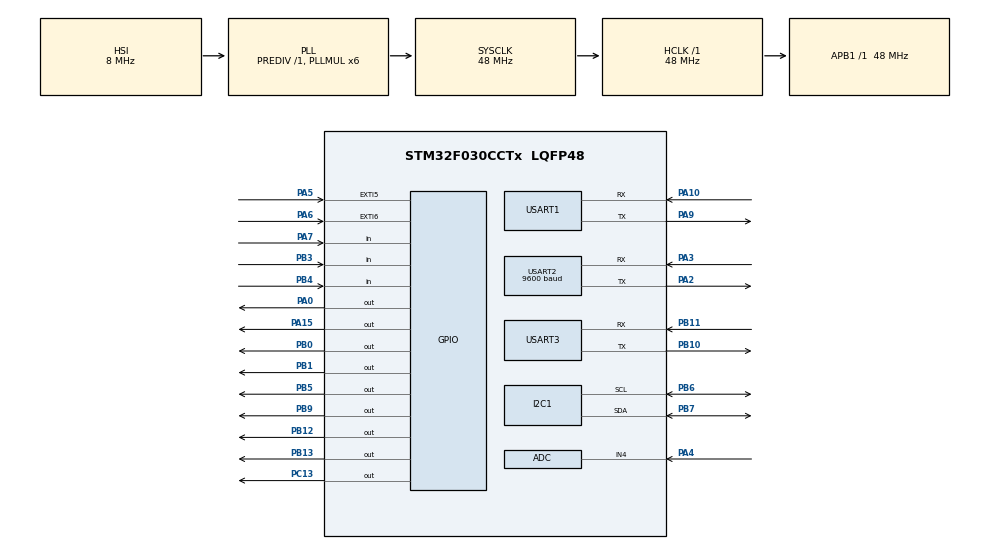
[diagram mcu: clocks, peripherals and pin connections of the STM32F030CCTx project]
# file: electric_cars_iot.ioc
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ADC.ClockPrescaler=ADC_CLOCK_SYNC_PCLK_DIV4
ADC.ContinuousConvMode=ENABLE
ADC.DMAContinuousRequests=ENABLE
ADC.DataAlign=ADC_DATAALIGN_RIGHT
ADC.DiscontinuousConvMode=DISABLE
ADC.EOCSelection=ADC_EOC_SINGLE_CONV
ADC.EnableAnalogWatchDog=false
ADC.ExternalTrigConv=ADC_SOFTWARE_START
ADC.ExternalTrigConvEdge=ADC_EXTERNALTRIGCONVEDGE_NONE
ADC.LowPowerAutoPowerOff=DISABLE
ADC.LowPowerAutoWait=DISABLE
ADC.Overrun=ADC_OVR_DATA_PRESERVED
ADC.Resolution=ADC_RESOLUTION_12B
ADC.SamplingTime=ADC_SAMPLETIME_7CYCLES_5
ADC.ScanConvMode=ADC_SCAN_DIRECTION_FORWARD
Dma.ADC.0.Direction=DMA_PERIPH_TO_MEMORY
Dma.ADC.0.Instance=DMA1_Channel1
Dma.ADC.0.MemDataAlignment=DMA_MDATAALIGN_WORD
Dma.ADC.0.MemInc=DMA_MINC_ENABLE
Dma.ADC.0.Mode=DMA_CIRCULAR
Dma.ADC.0.PeriphDataAlignment=DMA_PDATAALIGN_WORD
Dma.ADC.0.PeriphInc=DMA_PINC_DISABLE
Dma.ADC.0.Priority=DMA_PRIORITY_LOW
Dma.Request0=ADC
FREERTOS.INCLUDE_vTaskDelayUntil=0
FREERTOS.Tasks01=defaultTask,0,512,StartDefaultTask,Default,NULL,Dynamic,NULL,NULL;myTask02,0,256,StartTask02,Default,NULL,Dynamic,NULL,NULL
FREERTOS.configTICK_RATE_HZ=30
FREERTOS.configTOTAL_HEAP_SIZE=15000
FREERTOS.configUSE_IDLE_HOOK=1
FREERTOS.configUSE_TICK_HOOK=0
FREERTOS.configUSE_TIMERS=1
I2C1.Timing=0x20303E5D
IWDG.Prescaler=IWDG_PRESCALER_64
IWDG.Reload=3125
Mcu.Family=STM32F0
Mcu.Name=STM32F030CCTx
Mcu.Package=LQFP48
NVIC.DMA1_Channel1_IRQn=true\:3\:0\:false\:false\:true\:true\:false
NVIC.EXTI4_15_IRQn=true\:3\:0\:false\:false\:true\:true\:true
NVIC.TIM14_IRQn=true\:3\:0\:false\:false\:true\:true\:true
NVIC.TIM3_IRQn=true\:3\:0\:false\:false\:true\:true\:true
NVIC.TIM6_IRQn=true\:0\:0\:false\:false\:true\:false\:false
NVIC.TimeBase=TIM6_IRQn
NVIC.TimeBaseIP=TIM6
NVIC.USART1_IRQn=true\:0\:0\:true\:false\:true\:false\:true
NVIC.USART2_IRQn=true\:3\:0\:false\:false\:true\:true\:true
NVIC.USART3_6_IRQn=true\:3\:0\:false\:false\:true\:true\:true
PA0.Signal=GPIO_Output
PA10.Mode=Asynchronous
PA10.Signal=USART1_RX
PA13.Mode=Serial_Wire
PA13.Signal=SYS_SWDIO
PA14.Mode=Serial_Wire
PA14.Signal=SYS_SWCLK
PA15.Signal=GPIO_Output
PA2.Mode=Asynchronous
PA2.Signal=USART2_TX
PA3.Mode=Asynchronous
PA3.Signal=USART2_RX
PA4.Mode=IN4
PA4.Signal=ADC_IN4
PA5.Signal=GPXTI5
PA6.Signal=GPXTI6
PA7.Signal=GPIO_Input
PA9.Mode=Asynchronous
PA9.Signal=USART1_TX
PB0.Signal=GPIO_Output
PB1.Signal=GPIO_Output
PB10.Mode=Asynchronous
PB10.Signal=USART3_TX
PB11.Mode=Asynchronous
PB11.Signal=USART3_RX
PB12.Signal=GPIO_Output
PB13.Signal=GPIO_Output
PB3.Signal=GPIO_Input
PB4.Signal=GPIO_Input
PB5.Signal=GPIO_Output
PB6.Mode=I2C
PB6.Signal=I2C1_SCL
PB7.Mode=I2C
PB7.Signal=I2C1_SDA
PB9.Signal=GPIO_Output
PC13.Signal=GPIO_Output
PF0-OSC_IN.Mode=HSE-External-Oscillator
PF0-OSC_IN.Signal=RCC_OSC_IN
PF1-OSC_OUT.Mode=HSE-External-Oscillator
PF1-OSC_OUT.Signal=RCC_OSC_OUT
ProjectManager.HeapSize=0x200
ProjectManager.StackSize=0x400
ProjectManager.TargetToolchain=MDK-ARM V5
RCC.AHBFreq_Value=48000000
RCC.APB1Freq_Value=48000000
RCC.APB1TimFreq_Value=48000000
RCC.HCLKFreq_Value=48000000
RCC.I2c1ClockSelection=RCC_I2C1CLKSOURCE_SYSCLK
RCC.PLLMUL=RCC_PLL_MUL6
RCC.RTCClockSelection=RCC_RTCCLKSOURCE_HSE_DIV32
RCC.SYSCLKFreq_VALUE=48000000
RCC.SYSCLKSource=RCC_SYSCLKSOURCE_PLLCLK
RCC.Usart1ClockSelection=RCC_USART1CLKSOURCE_HSI
RTC.AsynchPrediv=99
RTC.SynchPrediv=2499
TIM1.Period=1
TIM1.Prescaler=48-1
TIM14.Period=100-1
TIM14.Prescaler=4800-1
TIM3.Period=10000-1
TIM3.Prescaler=4800-1
USART1.VirtualMode-Asynchronous=VM_ASYNC
USART1.WordLength=WORDLENGTH_8B
USART2.BaudRate=9600
USART2.VirtualMode-Asynchronous=VM_ASYNC
USART2.WordLength=WORDLENGTH_8B
USART3.VirtualMode-Asynchronous=VM_ASYNC
USART3.WordLength=WORDLENGTH_8B
VP_FREERTOS_VS_ENABLE.Mode=Enabled
VP_IWDG_VS_IWDG.Mode=IWDG_Activate
VP_RTC_VS_RTC_Activate.Mode=RTC_Enabled
VP_RTC_VS_RTC_Calendar.Mode=RTC_Calendar
VP_SYS_VS_tim6.Mode=TIM6
VP_TIM14_VS_ClockSourceINT.Mode=Enable_Timer
VP_TIM1_VS_ClockSourceINT.Mode=Internal
VP_TIM3_VS_ClockSourceINT.Mode=Internal
board=electric_cars_iot

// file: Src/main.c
/**
  ******************************************************************************
  * @file           : main.c
  * @brief          : Main program body
  ******************************************************************************
  * This notice applies to any and all portions of this file
  * that are not between comment pairs USER CODE BEGIN and
  * USER CODE END. Other portions of this file, whether
  * inserted by the user or by software development tools
  * are owned by their respective copyright owners.
  *
  * Copyright (c) 2018 STMicroelectronics International N.V.
  * All rights reserved.
  *
  * Redistribution and use in source and binary forms, with or without
  * modification, are permitted, provided that the following conditions are met:
  *
  * 1. Redistribution of source code must retain the above copyright notice,
  *    this list of conditions and the following disclaimer.
  * 2. Redistributions in binary form must reproduce the above copyright notice,
  *    this list of conditions and the following disclaimer in the documentation
  *    and/or other materials provided with the distribution.
  * 3. Neither the name of STMicroelectronics nor the names of other
  *    contributors to this software may be used to endorse or promote products
  *    derived from this software without specific written permission.
  * 4. This software, including modifications and/or derivative works of this
  *    software, must execute solely and exclusively on microcontroller or
  *    microprocessor devices manufactured by or for STMicroelectronics.
  * 5. Redistribution and use of this software other than as permitted under
  *    this license is void and will automatically terminate your rights under
  *    this license.
  *
  * THIS SOFTWARE IS PROVIDED BY STMICROELECTRONICS AND CONTRIBUTORS "AS IS"
  * AND ANY EXPRESS, IMPLIED OR STATUTORY WARRANTIES, INCLUDING, BUT NOT
  * LIMITED TO, THE IMPLIED WARRANTIES OF MERCHANTABILITY, FITNESS FOR A
  * PARTICULAR PURPOSE AND NON-INFRINGEMENT OF THIRD PARTY INTELLECTUAL PROPERTY
  * RIGHTS ARE DISCLAIMED TO THE FULLEST EXTENT PERMITTED BY LAW. IN NO EVENT
  * SHALL STMICROELECTRONICS OR CONTRIBUTORS BE LIABLE FOR ANY DIRECT, INDIRECT,
  * INCIDENTAL, SPECIAL, EXEMPLARY, OR CONSEQUENTIAL DAMAGES (INCLUDING, BUT NOT
  * LIMITED TO, PROCUREMENT OF SUBSTITUTE GOODS OR SERVICES; LOSS OF USE, DATA,
  * OR PROFITS; OR BUSINESS INTERRUPTION) HOWEVER CAUSED AND ON ANY THEORY OF
  * LIABILITY, WHETHER IN CONTRACT, STRICT LIABILITY, OR TORT (INCLUDING
  * NEGLIGENCE OR OTHERWISE) ARISING IN ANY WAY OUT OF THE USE OF THIS SOFTWARE,
  * EVEN IF ADVISED OF THE POSSIBILITY OF SUCH DAMAGE.
  *
  ******************************************************************************
  */
#include "main.h"
#include "stm32f0xx_hal.h"
#include "cmsis_os.h"

/* USER CODE BEGIN Includes */
#include "usart.h"
#include "Iot_Hub.h"
#include "protocol.h"
#include "adc.h"
#include "exti.h"
#include "voice.h"
#include "gpio.h"
#include "flash.h"
#include "bt_app.h"
#include "queen.h"
#include "control_app.h"

/* USER CODE END Includes */

ADC_HandleTypeDef hadc;
DMA_HandleTypeDef hdma_adc;

I2C_HandleTypeDef hi2c1;

IWDG_HandleTypeDef hiwdg;

RTC_HandleTypeDef hrtc;

TIM_HandleTypeDef htim1;
TIM_HandleTypeDef htim3;
TIM_HandleTypeDef htim14;

UART_HandleTypeDef huart1;
UART_HandleTypeDef huart2;
UART_HandleTypeDef huart3;

osThreadId defaultTaskHandle;
osThreadId myTask02Handle;

/* USER CODE BEGIN PV */
/* Private variables ---------------------------------------------------------*/
uint8_t usart1_recbuf, usart2_recbuf,usart3_recbuf;
uint8_t tim3_delay3s;
uint16_t tim14_delay900ms,tim14_delay500ms,tim14_delay10ms, tim14_delay4s,tim14_delay8s;
uint8_t flag_delay3s, flag_delay1s, flag_sendlock;
uint32_t adc_val[64];
uint16_t batvol;
uint64_t rotate_bak, mileage_bak, shake_bak;
uint8_t first_pwr;

extern uint8_t login_protect_timeout;
extern uint8_t flag_alarm;
extern uint8_t flag_delay8s;

/* USER CODE END PV */

void SystemClock_Config(void);
static void MX_GPIO_Init(void);
static void MX_DMA_Init(void);
static void MX_USART1_UART_Init(void);
static void MX_USART2_UART_Init(void);
static void MX_USART3_UART_Init(void);
static void MX_ADC_Init(void);
static void MX_TIM3_Init(void);
static void MX_TIM1_Init(void);
static void MX_TIM14_Init(void);
static void MX_I2C1_Init(void);
static void MX_IWDG_Init(void);
static void MX_RTC_Init(void);
void StartDefaultTask(void const * argument);
void StartTask02(void const * argument);

/* USER CODE BEGIN 0 */
void delay_us(uint32_t n_10us);
void init_all(void)
{
	init_flash();
 	bt_init();
}
/* USER CODE END 0 */

int main(void)
{
  HAL_Init();
  SystemClock_Config();

  MX_GPIO_Init();
  MX_DMA_Init();
  MX_USART1_UART_Init();
  MX_USART2_UART_Init();
  MX_USART3_UART_Init();
  MX_I2C1_Init();
  MX_ADC_Init();
  MX_TIM3_Init();
  MX_TIM1_Init();
  MX_TIM14_Init();
  MX_IWDG_Init();
  MX_RTC_Init();

  init_all();

  osThreadDef(defaultTask, StartDefaultTask, osPriorityNormal, 0, 2048);
  defaultTaskHandle = osThreadCreate(osThread(defaultTask), NULL);

  osThreadDef(myTask02, StartTask02, osPriorityNormal, 0, 1024);
  myTask02Handle = osThreadCreate(osThread(myTask02), NULL);

  osKernelStart();

  while (1)
  {
  }

}

void SystemClock_Config(void)
{

  RCC_OscInitTypeDef RCC_OscInitStruct;
  RCC_ClkInitTypeDef RCC_ClkInitStruct;
  RCC_PeriphCLKInitTypeDef PeriphClkInit;

    /**Initializes the CPU, AHB and APB busses clocks
    */
  RCC_OscInitStruct.OscillatorType = RCC_OSCILLATORTYPE_HSI|RCC_OSCILLATORTYPE_LSI
                              |RCC_OSCILLATORTYPE_HSE;
  RCC_OscInitStruct.HSEState = RCC_HSE_ON;
  RCC_OscInitStruct.HSIState = RCC_HSI_ON;
  RCC_OscInitStruct.HSICalibrationValue = 16;
  RCC_OscInitStruct.LSIState = RCC_LSI_ON;
  RCC_OscInitStruct.PLL.PLLState = RCC_PLL_ON;
  RCC_OscInitStruct.PLL.PLLSource = RCC_PLLSOURCE_HSI;
  RCC_OscInitStruct.PLL.PLLMUL = RCC_PLL_MUL6;
  RCC_OscInitStruct.PLL.PREDIV = RCC_PREDIV_DIV1;
  if (HAL_RCC_OscConfig(&RCC_OscInitStruct) != HAL_OK)
  {
    _Error_Handler(__FILE__, __LINE__);
  }

    /**Initializes the CPU, AHB and APB busses clocks
    */
  RCC_ClkInitStruct.ClockType = RCC_CLOCKTYPE_HCLK|RCC_CLOCKTYPE_SYSCLK
                              |RCC_CLOCKTYPE_PCLK1;
  RCC_ClkInitStruct.SYSCLKSource = RCC_SYSCLKSOURCE_PLLCLK;
  RCC_ClkInitStruct.AHBCLKDivider = RCC_SYSCLK_DIV1;
  RCC_ClkInitStruct.APB1CLKDivider = RCC_HCLK_DIV1;

  if (HAL_RCC_ClockConfig(&RCC_ClkInitStruct, FLASH_LATENCY_1) != HAL_OK)
  {
    _Error_Handler(__FILE__, __LINE__);
  }

  PeriphClkInit.PeriphClockSelection = RCC_PERIPHCLK_USART1|RCC_PERIPHCLK_I2C1
                              |RCC_PERIPHCLK_RTC;
  PeriphClkInit.Usart1ClockSelection = RCC_USART1CLKSOURCE_HSI;
  PeriphClkInit.I2c1ClockSelection = RCC_I2C1CLKSOURCE_SYSCLK;
  PeriphClkInit.RTCClockSelection = RCC_RTCCLKSOURCE_HSE_DIV32;
  if (HAL_RCCEx_PeriphCLKConfig(&PeriphClkInit) != HAL_OK)
  {
    _Error_Handler(__FILE__, __LINE__);
  }

    /**Configure the Systick interrupt time
    */
  HAL_SYSTICK_Config(HAL_RCC_GetHCLKFreq()/1000);

    /**Configure the Systick
    */
  HAL_SYSTICK_CLKSourceConfig(SYSTICK_CLKSOURCE_HCLK);

  /* SysTick_IRQn interrupt configuration */
  HAL_NVIC_SetPriority(SysTick_IRQn, 3, 0);
}

/* ADC init function */
static void MX_ADC_Init(void)
{

  ADC_ChannelConfTypeDef sConfig;

    /**Configure the global features of the ADC (Clock, Resolution, Data Alignment and number of conversion)
    */
  hadc.Instance = ADC1;
  hadc.Init.ClockPrescaler = ADC_CLOCK_SYNC_PCLK_DIV4;
  hadc.Init.Resolution = ADC_RESOLUTION_12B;
  hadc.Init.DataAlign = ADC_DATAALIGN_RIGHT;
  hadc.Init.ScanConvMode = ADC_SCAN_DIRECTION_FORWARD;
  hadc.Init.EOCSelection = ADC_EOC_SINGLE_CONV;
  hadc.Init.LowPowerAutoWait = DISABLE;
  hadc.Init.LowPowerAutoPowerOff = DISABLE;
  hadc.Init.ContinuousConvMode = ENABLE;
  hadc.Init.DiscontinuousConvMode = DISABLE;
  hadc.Init.ExternalTrigConv = ADC_SOFTWARE_START;
  hadc.Init.ExternalTrigConvEdge = ADC_EXTERNALTRIGCONVEDGE_NONE;
  hadc.Init.DMAContinuousRequests = ENABLE;
  hadc.Init.Overrun = ADC_OVR_DATA_PRESERVED;
  if (HAL_ADC_Init(&hadc) != HAL_OK)
  {
    _Error_Handler(__FILE__, __LINE__);
  }

    /**Configure for the selected ADC regular channel to be converted.
    */
  sConfig.Channel = ADC_CHANNEL_4;
  sConfig.Rank = ADC_RANK_CHANNEL_NUMBER;
  sConfig.SamplingTime = ADC_SAMPLETIME_7CYCLES_5;
  if (HAL_ADC_ConfigChannel(&hadc, &sConfig) != HAL_OK)
  {
    _Error_Handler(__FILE__, __LINE__);
  }

}

/* IWDG init function */
static void MX_IWDG_Init(void)
{

  hiwdg.Instance = IWDG;
  hiwdg.Init.Prescaler = IWDG_PRESCALER_64;
  hiwdg.Init.Window = 4095;
  hiwdg.Init.Reload = 3125;
  if (HAL_IWDG_Init(&hiwdg) != HAL_OK)
  {
    _Error_Handler(__FILE__, __LINE__);
  }

}

/* RTC init function */
static void MX_RTC_Init(void)
{

  RTC_TimeTypeDef sTime;
  RTC_DateTypeDef sDate;

    /**Initialize RTC Only
    */
  hrtc.Instance = RTC;
  hrtc.Init.HourFormat = RTC_HOURFORMAT_24;
  hrtc.Init.AsynchPrediv = 99;
  hrtc.Init.SynchPrediv = 2499;
  hrtc.Init.OutPut = RTC_OUTPUT_DISABLE;
  hrtc.Init.OutPutPolarity = RTC_OUTPUT_POLARITY_HIGH;
  hrtc.Init.OutPutType = RTC_OUTPUT_TYPE_OPENDRAIN;
  if (HAL_RTC_Init(&hrtc) != HAL_OK)
  {
    _Error_Handler(__FILE__, __LINE__);
  }

    /**Initialize RTC and set the Time and Date
    */
  sTime.Hours = 0x0;
  sTime.Minutes = 0x0;
  sTime.Seconds = 0x0;
  sTime.DayLightSaving = RTC_DAYLIGHTSAVING_NONE;
  sTime.StoreOperation = RTC_STOREOPERATION_RESET;
  if (HAL_RTC_SetTime(&hrtc, &sTime, RTC_FORMAT_BCD) != HAL_OK)
  {
    _Error_Handler(__FILE__, __LINE__);
  }

  sDate.WeekDay = RTC_WEEKDAY_MONDAY;
  sDate.Month = RTC_MONTH_JANUARY;
  sDate.Date = 0x1;
  sDate.Year = 0x0;

  if (HAL_RTC_SetDate(&hrtc, &sDate, RTC_FORMAT_BCD) != HAL_OK)
  {
    _Error_Handler(__FILE__, __LINE__);
  }

}

/* TIM1 init function */
static void MX_TIM1_Init(void)
{

  TIM_ClockConfigTypeDef sClockSourceConfig;
  TIM_MasterConfigTypeDef sMasterConfig;

  htim1.Instance = TIM1;
  htim1.Init.Prescaler = 48-1;
  htim1.Init.CounterMode = TIM_COUNTERMODE_UP;
  htim1.Init.Period = 1;
  htim1.Init.ClockDivision = TIM_CLOCKDIVISION_DIV1;
  htim1.Init.RepetitionCounter = 0;
  htim1.Init.AutoReloadPreload = TIM_AUTORELOAD_PRELOAD_DISABLE;
  if (HAL_TIM_Base_Init(&htim1) != HAL_OK)
  {
    _Error_Handler(__FILE__, __LINE__);
  }

  sClockSourceConfig.ClockSource = TIM_CLOCKSOURCE_INTERNAL;
  if (HAL_TIM_ConfigClockSource(&htim1, &sClockSourceConfig) != HAL_OK)
  {
    _Error_Handler(__FILE__, __LINE__);
  }

  sMasterConfig.MasterOutputTrigger = TIM_TRGO_RESET;
  sMasterConfig.MasterSlaveMode = TIM_MASTERSLAVEMODE_DISABLE;
  if (HAL_TIMEx_MasterConfigSynchronization(&htim1, &sMasterConfig) != HAL_OK)
  {
    _Error_Handler(__FILE__, __LINE__);
  }

}

/* TIM3 init function */
static void MX_TIM3_Init(void)
{

  TIM_ClockConfigTypeDef sClockSourceConfig;
  TIM_MasterConfigTypeDef sMasterConfig;

  htim3.Instance = TIM3;
  htim3.Init.Prescaler = 4800-1;
  htim3.Init.CounterMode = TIM_COUNTERMODE_UP;
  htim3.Init.Period = 10000-1;
  htim3.Init.ClockDivision = TIM_CLOCKDIVISION_DIV1;
  htim3.Init.AutoReloadPreload = TIM_AUTORELOAD_PRELOAD_DISABLE;
  if (HAL_TIM_Base_Init(&htim3) != HAL_OK)
  {
    _Error_Handler(__FILE__, __LINE__);
  }

  sClockSourceConfig.ClockSource = TIM_CLOCKSOURCE_INTERNAL;
  if (HAL_TIM_ConfigClockSource(&htim3, &sClockSourceConfig) != HAL_OK)
  {
    _Error_Handler(__FILE__, __LINE__);
  }

  sMasterConfig.MasterOutputTrigger = TIM_TRGO_RESET;
  sMasterConfig.MasterSlaveMode = TIM_MASTERSLAVEMODE_DISABLE;
  if (HAL_TIMEx_MasterConfigSynchronization(&htim3, &sMasterConfig) != HAL_OK)
  {
    _Error_Handler(__FILE__, __LINE__);
  }

}

/* TIM14 init function */
static void MX_TIM14_Init(void)
{

  htim14.Instance = TIM14;
  htim14.Init.Prescaler = 4800-1;
  htim14.Init.CounterMode = TIM_COUNTERMODE_UP;
  htim14.Init.Period = 10-1;
  htim14.Init.ClockDivision = TIM_CLOCKDIVISION_DIV1;
  htim14.Init.AutoReloadPreload = TIM_AUTORELOAD_PRELOAD_DISABLE;
  if (HAL_TIM_Base_Init(&htim14) != HAL_OK)
  {
    _Error_Handler(__FILE__, __LINE__);
  }

}
static void MX_I2C1_Init(void)
{

  hi2c1.Instance = I2C1;
  hi2c1.Init.Timing = 0x20303E5D;
  hi2c1.Init.OwnAddress1 = 0;
  hi2c1.Init.AddressingMode = I2C_ADDRESSINGMODE_7BIT;
  hi2c1.Init.DualAddressMode = I2C_DUALADDRESS_DISABLE;
  hi2c1.Init.OwnAddress2 = 0;
  hi2c1.Init.OwnAddress2Masks = I2C_OA2_NOMASK;
  hi2c1.Init.GeneralCallMode = I2C_GENERALCALL_DISABLE;
  hi2c1.Init.NoStretchMode = I2C_NOSTRETCH_DISABLE;
  if (HAL_I2C_Init(&hi2c1) != HAL_OK)
  {
    _Error_Handler(__FILE__, __LINE__);
  }

    /**Configure Analogue filter
    */
  if (HAL_I2CEx_ConfigAnalogFilter(&hi2c1, I2C_ANALOGFILTER_ENABLE) != HAL_OK)
  {
    _Error_Handler(__FILE__, __LINE__);
  }

    /**Configure Digital filter
    */
  if (HAL_I2CEx_ConfigDigitalFilter(&hi2c1, 0) != HAL_OK)
  {
    _Error_Handler(__FILE__, __LINE__);
  }

}

/* USART1 init function */
static void MX_USART1_UART_Init(void)
{

  huart1.Instance = USART1;
  huart1.Init.BaudRate = 115200;
  huart1.Init.WordLength = UART_WORDLENGTH_8B;
  huart1.Init.StopBits = UART_STOPBITS_1;
  huart1.Init.Parity = UART_PARITY_NONE;
  huart1.Init.Mode = UART_MODE_TX_RX;
  huart1.Init.HwFlowCtl = UART_HWCONTROL_NONE;
  huart1.Init.OverSampling = UART_OVERSAMPLING_16;
  huart1.Init.OneBitSampling = UART_ONE_BIT_SAMPLE_DISABLE;
  huart1.AdvancedInit.AdvFeatureInit = UART_ADVFEATURE_NO_INIT;
  if (HAL_UART_Init(&huart1) != HAL_OK)
  {
    _Error_Handler(__FILE__, __LINE__);
  }
  HAL_UART_Receive_IT(&huart1, (uint8_t *)&usart1_recbuf, 1);

}

/* USART2 init function */
static void MX_USART2_UART_Init(void)
{

  huart2.Instance = USART2;
  huart2.Init.BaudRate = 9600;
  huart2.Init.WordLength = UART_WORDLENGTH_8B;
  huart2.Init.StopBits = UART_STOPBITS_1;
  huart2.Init.Parity = UART_PARITY_NONE;
  huart2.Init.Mode = UART_MODE_TX_RX;
  huart2.Init.HwFlowCtl = UART_HWCONTROL_NONE;
  huart2.Init.OverSampling = UART_OVERSAMPLING_16;
  huart2.Init.OneBitSampling = UART_ONE_BIT_SAMPLE_DISABLE;
  huart2.AdvancedInit.AdvFeatureInit = UART_ADVFEATURE_NO_INIT;
  if (HAL_UART_Init(&huart2) != HAL_OK)
  {
    _Error_Handler(__FILE__, __LINE__);
  }

}

/* USART3 init function */
static void MX_USART3_UART_Init(void)
{
  huart3.Instance = USART3;
  huart3.Init.BaudRate = 115200;
  huart3.Init.WordLength = UART_WORDLENGTH_8B;
  huart3.Init.StopBits = UART_STOPBITS_1;
  huart3.Init.Parity = UART_PARITY_NONE;
  huart3.Init.Mode = UART_MODE_TX_RX;
  huart3.Init.HwFlowCtl = UART_HWCONTROL_NONE;
  huart3.Init.OverSampling = UART_OVERSAMPLING_16;
  huart3.Init.OneBitSampling = UART_ONE_BIT_SAMPLE_DISABLE;
  huart3.AdvancedInit.AdvFeatureInit = UART_ADVFEATURE_NO_INIT;
  if (HAL_UART_Init(&huart3) != HAL_OK)
  {
    _Error_Handler(__FILE__, __LINE__);
  }

}

static void MX_DMA_Init(void)
{
  /* DMA controller clock enable */
  __HAL_RCC_DMA1_CLK_ENABLE();

  /* DMA interrupt init */
  /* DMA1_Channel1_IRQn interrupt configuration */
  HAL_NVIC_SetPriority(DMA1_Channel1_IRQn, 3, 0);
  HAL_NVIC_EnableIRQ(DMA1_Channel1_IRQn);

}

/** Configure pins as
        * Analog
        * Input
        * Output
        * EVENT_OUT
        * EXTI
*/
static void MX_GPIO_Init(void)
{

  GPIO_InitTypeDef GPIO_InitStruct;

  /* GPIO Ports Clock Enable */
  __HAL_RCC_GPIOC_CLK_ENABLE();
  __HAL_RCC_GPIOF_CLK_ENABLE();
  __HAL_RCC_GPIOA_CLK_ENABLE();
  __HAL_RCC_GPIOB_CLK_ENABLE();

  /*Configure GPIO pin Output Level */
  HAL_GPIO_WritePin(GPIOC, GPIO_PIN_13, GPIO_PIN_RESET);

  /*Configure GPIO pin Output Level */
  HAL_GPIO_WritePin(GPIOA, GPIO_PIN_0|GPIO_PIN_1|GPIO_PIN_11|GPIO_PIN_15|GPIO_PIN_12, GPIO_PIN_RESET);

  /*Configure GPIO pin Output Level */
  HAL_GPIO_WritePin(GPIOB, GPIO_PIN_0|GPIO_PIN_1|GPIO_PIN_12|GPIO_PIN_13
                          |GPIO_PIN_5|GPIO_PIN_9, GPIO_PIN_RESET);

  /*Configure GPIO pin : PC13 */
  GPIO_InitStruct.Pin = GPIO_PIN_13;
  GPIO_InitStruct.Mode = GPIO_MODE_OUTPUT_PP;
  GPIO_InitStruct.Pull = GPIO_NOPULL;
  GPIO_InitStruct.Speed = GPIO_SPEED_FREQ_LOW;
  HAL_GPIO_Init(GPIOC, &GPIO_InitStruct);

  /*Configure GPIO pins : PA0 PA15 */
  GPIO_InitStruct.Pin = GPIO_PIN_0|GPIO_PIN_1|GPIO_PIN_11|GPIO_PIN_15|GPIO_PIN_12;
  GPIO_InitStruct.Mode = GPIO_MODE_OUTPUT_PP;
  GPIO_InitStruct.Pull = GPIO_NOPULL;
  GPIO_InitStruct.Speed = GPIO_SPEED_FREQ_LOW;
  HAL_GPIO_Init(GPIOA, &GPIO_InitStruct);

  /*Configure GPIO pins : PA5 PA6 */
  GPIO_InitStruct.Pin = GPIO_PIN_5|GPIO_PIN_6|GPIO_PIN_8;
  GPIO_InitStruct.Mode = GPIO_MODE_IT_RISING;
  GPIO_InitStruct.Pull = GPIO_NOPULL;
  HAL_GPIO_Init(GPIOA, &GPIO_InitStruct);

  /*Configure GPIO pin : PA7 */
  GPIO_InitStruct.Pin = GPIO_PIN_7;
  GPIO_InitStruct.Mode = GPIO_MODE_INPUT;
  GPIO_InitStruct.Pull = GPIO_NOPULL;
  HAL_GPIO_Init(GPIOA, &GPIO_InitStruct);

  /*Configure GPIO pins : PB0 PB1 PB12 PB13
                           PB5 PB9 */
  GPIO_InitStruct.Pin = GPIO_PIN_0|GPIO_PIN_1|GPIO_PIN_12|GPIO_PIN_13
                          |GPIO_PIN_5|GPIO_PIN_9;
  GPIO_InitStruct.Mode = GPIO_MODE_OUTPUT_PP;
  GPIO_InitStruct.Pull = GPIO_NOPULL;
  GPIO_InitStruct.Speed = GPIO_SPEED_FREQ_LOW;
  HAL_GPIO_Init(GPIOB, &GPIO_InitStruct);

  /*Configure GPIO pins : PB3 PB4 */
  GPIO_InitStruct.Pin = GPIO_PIN_3|GPIO_PIN_4;
  GPIO_InitStruct.Mode = GPIO_MODE_INPUT;
  GPIO_InitStruct.Pull = GPIO_NOPULL;
  HAL_GPIO_Init(GPIOB, &GPIO_InitStruct);

  /* EXTI interrupt init*/
  HAL_NVIC_SetPriority(EXTI4_15_IRQn, 3, 0);
  HAL_NVIC_EnableIRQ(EXTI4_15_IRQn);

}

/* USER CODE BEGIN 4 */
/**
  * @brief  Rx Transfer completed callback
  * @param  UartHandle: UART handle
  * @note   This example shows a simple way to report end of DMA Rx transfer, and
  *         you can add your own implementation.
  * @retval None
  */
void HAL_UART_RxCpltCallback(UART_HandleTypeDef *UartHandle)
{
  /* Set transmission flag: transfer complete */
	if (UartHandle->Instance == USART1)
	{
		module_recv_buffer[module_recv_write_index] = usart1_recbuf; //将接收到的字符串存到缓存中
		module_recv_write_index++;
		if(module_recv_write_index >= MODULE_BUFFER_SIZE)       			//如果缓存满,将缓存指针指向缓存的首地址
		{
			module_recv_write_index = 0;
		}
		 HAL_UART_Receive_IT(&huart1, (uint8_t *)&usart1_recbuf, 1);
       	}
	if (UartHandle->Instance == USART2)
	{
		Uart2_buf.Data[0]= usart2_recbuf;
		PushElement(&RxUart2_Queue,Uart2_buf,1);//将接收到的数据压入队列中
		HAL_UART_Receive_IT(&huart2, &usart2_recbuf, 1);
	}
	if (UartHandle->Instance == USART3)
	{
		Uart3_buf.Data[0]= usart3_recbuf;
		PushElement(&RxUart3_Queue,Uart3_buf,1);//将接收到的数据压入队列中
		HAL_UART_Receive_IT(&huart3, &usart3_recbuf, 1);
	}
}
/* USER CODE END 4 */

/* StartDefaultTask function */
void StartDefaultTask(void const * argument)
{
  /* USER CODE BEGIN 5 */
  	first_pwr = 1;
  	InitCircleQueue(&at_send_Queue);	                           //初始化队列

	/* Infinite loop */
	for(;;)
	{
		voice_process();
		if(g_flash.mode==0)	//正常模式
		{
			at_process();
		}
		else if(g_flash.mode==1)	//测试模式
		{
			test_process();
	    	}
		osDelay(1);
	}
  /* USER CODE END 5 */
}

/* StartTask02 function */
void StartTask02(void const * argument)
{
  /* USER CODE BEGIN StartTask02 */
	HAL_TIM_Base_Start_IT(&htim14);
  	HAL_TIM_Base_Start_IT(&htim3);
	HAL_ADCEx_Calibration_Start(&hadc);
	HAL_ADC_Start_DMA(&hadc, (uint32_t*)&adc_val, 64);
	InitCircleQueue(&RxUart2_Queue);	                           //初始化队列
	HAL_UART_Receive_IT(&huart2, (uint8_t *)&usart2_recbuf, 1);
	InitCircleQueue(&RxUart3_Queue);	                           //初始化队列
	HAL_UART_Receive_IT(&huart3, (uint8_t *)&usart3_recbuf, 1);
	HAL_Delay(2000);
	flag_alarm = 0;	//延时一会再启动震动告警

  for(;;)
  {
  	if(g_flash.mode==0)	//正常模式
	{
	        tangze_lock_bike();
	        tangze_unlock_bike();
	        battery_lock();
	        motorlock_process();
	        shake_process();
	//	key_check_process();
		gsm_led_process();
	        gps_led_process();
		gb_speed_process();
  	}
	uart2_process();
	uart3_process();

        osDelay(1);
  }

}

void HAL_TIM_PeriodElapsedCallback(TIM_HandleTypeDef *htim)
{
  /* USER CODE BEGIN Callback 0 */
	if (htim->Instance == TIM14)
	{
		if (flag_delay900ms)
			tim14_delay900ms ++;
		if (tim14_delay900ms >= 800)
		{
			tim14_delay900ms = 0;
			if (flag_lock == 1)
			{
				flag_delay_lock = 1;
			}
			else if (flag_lock == 2)
			{
				flag_delay_unlock = 1;
			}
		}

		if (flag_delay500ms)
			tim14_delay500ms ++;
		if (tim14_delay500ms >= 500)
		{
			tim14_delay500ms = 0;
			flag_batlock = 1;
		}
		if (flag_delay10ms)
			tim14_delay10ms ++;
		if (tim14_delay10ms >= 1)
		{
			tim14_delay10ms = 0;
			flag_motorlock = 1;
		}
		if (flag_delay4s)
			tim14_delay4s++;
		if (tim14_delay4s >= 4000)
		{
			tim14_delay4s = 0;
			flag_motorlock2 = 1;
		}

		if (flag_delay8s)
			tim14_delay8s++;
		if (tim14_delay8s >= 8000)
		{
			tim14_delay8s = 0;
			flag_alarm = 0;
			flag_delay8s = 0;
		}

	}

	/* USER CODE END Callback 0 */
	if (htim->Instance == TIM6)
	{
	HAL_IncTick();
	}
  	/* USER CODE BEGIN Callback 1 */
	if (htim->Instance == htim3.Instance)
	{
		tim3_delay3s++;

		if (tim3_delay3s >= 3)
		{
			tim3_delay3s = 0;
			flag_delay3s = 1;
		}
		flag_delay1s = 1;

		diff_rotate = rotate_count - rotate_bak;
		diff_mileage = mileage_count - mileage_bak;
		diff_shake = shake_count - shake_bak;

		rotate_bak = rotate_count;
		mileage_bak = mileage_count;
		shake_bak = shake_count;

//		Logln(D_INFO,"Feed WatchDog");
		HAL_IWDG_Refresh(&hiwdg);//5s内必须喂看门狗，不然系统会复位

	}
  /* USER CODE END Callback 1 */
}

void _Error_Handler(char *file, int line)
{
  while(1)
  {
  }
}

/************************ (C) COPYRIGHT STMicroelectronics *****END OF FILE****/

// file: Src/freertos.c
/**
  ******************************************************************************
  * File Name          : freertos.c
  * Description        : Code for freertos applications
  ******************************************************************************
  * This notice applies to any and all portions of this file
  * that are not between comment pairs USER CODE BEGIN and
  * USER CODE END. Other portions of this file, whether
  * inserted by the user or by software development tools
  * are owned by their respective copyright owners.
  *
  * Copyright (c) 2018 STMicroelectronics International N.V.
  * All rights reserved.
  *
  * Redistribution and use in source and binary forms, with or without
  * modification, are permitted, provided that the following conditions are met:
  *
  * 1. Redistribution of source code must retain the above copyright notice,
  *    this list of conditions and the following disclaimer.
  * 2. Redistributions in binary form must reproduce the above copyright notice,
  *    this list of conditions and the following disclaimer in the documentation
  *    and/or other materials provided with the distribution.
  * 3. Neither the name of STMicroelectronics nor the names of other
  *    contributors to this software may be used to endorse or promote products
  *    derived from this software without specific written permission.
  * 4. This software, including modifications and/or derivative works of this
  *    software, must execute solely and exclusively on microcontroller or
  *    microprocessor devices manufactured by or for STMicroelectronics.
  * 5. Redistribution and use of this software other than as permitted under
  *    this license is void and will automatically terminate your rights under
  *    this license.
  *
  * THIS SOFTWARE IS PROVIDED BY STMICROELECTRONICS AND CONTRIBUTORS "AS IS"
  * AND ANY EXPRESS, IMPLIED OR STATUTORY WARRANTIES, INCLUDING, BUT NOT
  * LIMITED TO, THE IMPLIED WARRANTIES OF MERCHANTABILITY, FITNESS FOR A
  * PARTICULAR PURPOSE AND NON-INFRINGEMENT OF THIRD PARTY INTELLECTUAL PROPERTY
  * RIGHTS ARE DISCLAIMED TO THE FULLEST EXTENT PERMITTED BY LAW. IN NO EVENT
  * SHALL STMICROELECTRONICS OR CONTRIBUTORS BE LIABLE FOR ANY DIRECT, INDIRECT,
  * INCIDENTAL, SPECIAL, EXEMPLARY, OR CONSEQUENTIAL DAMAGES (INCLUDING, BUT NOT
  * LIMITED TO, PROCUREMENT OF SUBSTITUTE GOODS OR SERVICES; LOSS OF USE, DATA,
  * OR PROFITS; OR BUSINESS INTERRUPTION) HOWEVER CAUSED AND ON ANY THEORY OF
  * LIABILITY, WHETHER IN CONTRACT, STRICT LIABILITY, OR TORT (INCLUDING
  * NEGLIGENCE OR OTHERWISE) ARISING IN ANY WAY OUT OF THE USE OF THIS SOFTWARE,
  * EVEN IF ADVISED OF THE POSSIBILITY OF SUCH DAMAGE.
  *
  ******************************************************************************
  */

#include "FreeRTOS.h"
#include "task.h"

/* Hook prototypes */
void vApplicationIdleHook(void);

/* USER CODE BEGIN 2 */
__weak void vApplicationIdleHook( void )
{
   /* vApplicationIdleHook() will only be called if configUSE_IDLE_HOOK is set
   to 1 in FreeRTOSConfig.h. It will be called on each iteration of the idle
   task. It is essential that code added to this hook function never attempts
   to block in any way (for example, call xQueueReceive() with a block time
   specified, or call vTaskDelay()). If the application makes use of the
   vTaskDelete() API function (as this demo application does) then it is also
   important that vApplicationIdleHook() is permitted to return to its calling
   function, because it is the responsibility of the idle task to clean up
   memory allocated by the kernel to any task that has since been deleted. */
}
/* USER CODE END 2 */

/************************ (C) COPYRIGHT STMicroelectronics *****END OF FILE****/
